VERSION 5.7 ;
  NOWIREEXTENSIONATPIN ON ;
  DIVIDERCHAR "/" ;
  BUSBITCHARS "[]" ;
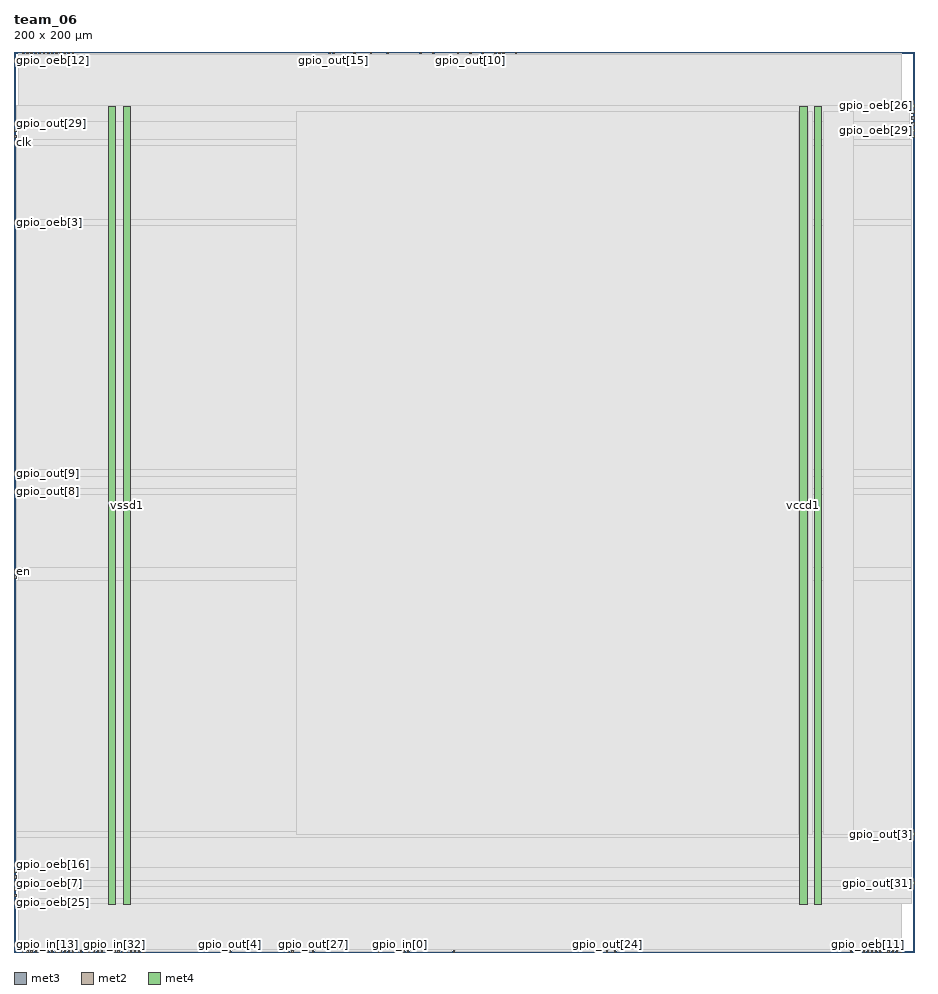
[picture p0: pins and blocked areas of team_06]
MACRO team_06
  CLASS BLOCK ;
  FOREIGN team_06 ;
  ORIGIN 0.000 0.000 ;
  SIZE 200.000 BY 200.000 ;
  PIN clk
    DIRECTION INPUT ;
    USE SIGNAL ;
    ANTENNAGATEAREA 1.286700 ;
    ANTENNADIFFAREA 0.434700 ;
    PORT
      LAYER met3 ;
        RECT 0.000 179.560 0.600 180.160 ;
    END
  END clk
  PIN en
    DIRECTION INPUT ;
    USE SIGNAL ;
    ANTENNAGATEAREA 0.647700 ;
    ANTENNADIFFAREA 0.434700 ;
    PORT
      LAYER met3 ;
        RECT 0.000 84.360 0.600 84.960 ;
    END
  END en
  PIN gpio_in[0]
    DIRECTION INPUT ;
    USE SIGNAL ;
    ANTENNAGATEAREA 0.647700 ;
    ANTENNADIFFAREA 0.434700 ;
    PORT
      LAYER met2 ;
        RECT 85.650 0.000 85.930 0.280 ;
    END
  END gpio_in[0]
  PIN gpio_in[10]
    DIRECTION INPUT ;
    USE SIGNAL ;
    PORT
      LAYER met2 ;
        RECT 1.930 0.000 2.210 0.280 ;
    END
  END gpio_in[10]
  PIN gpio_in[11]
    DIRECTION INPUT ;
    USE SIGNAL ;
    PORT
      LAYER met2 ;
        RECT 2.850 0.000 3.130 0.280 ;
    END
  END gpio_in[11]
  PIN gpio_in[12]
    DIRECTION INPUT ;
    USE SIGNAL ;
    PORT
      LAYER met2 ;
        RECT 3.770 0.000 4.050 0.280 ;
    END
  END gpio_in[12]
  PIN gpio_in[13]
    DIRECTION INPUT ;
    USE SIGNAL ;
    PORT
      LAYER met2 ;
        RECT 4.690 0.000 4.970 0.280 ;
    END
  END gpio_in[13]
  PIN gpio_in[14]
    DIRECTION INPUT ;
    USE SIGNAL ;
    PORT
      LAYER met2 ;
        RECT 5.610 0.000 5.890 0.280 ;
    END
  END gpio_in[14]
  PIN gpio_in[15]
    DIRECTION INPUT ;
    USE SIGNAL ;
    PORT
      LAYER met2 ;
        RECT 6.530 0.000 6.810 0.280 ;
    END
  END gpio_in[15]
  PIN gpio_in[16]
    DIRECTION INPUT ;
    USE SIGNAL ;
    PORT
      LAYER met2 ;
        RECT 7.450 0.000 7.730 0.280 ;
    END
  END gpio_in[16]
  PIN gpio_in[17]
    DIRECTION INPUT ;
    USE SIGNAL ;
    PORT
      LAYER met2 ;
        RECT 8.370 0.000 8.650 0.280 ;
    END
  END gpio_in[17]
  PIN gpio_in[18]
    DIRECTION INPUT ;
    USE SIGNAL ;
    PORT
      LAYER met2 ;
        RECT 9.290 0.000 9.570 0.280 ;
    END
  END gpio_in[18]
  PIN gpio_in[19]
    DIRECTION INPUT ;
    USE SIGNAL ;
    PORT
      LAYER met2 ;
        RECT 10.210 0.000 10.490 0.280 ;
    END
  END gpio_in[19]
  PIN gpio_in[1]
    DIRECTION INPUT ;
    USE SIGNAL ;
    ANTENNAGATEAREA 0.647700 ;
    ANTENNADIFFAREA 0.434700 ;
    PORT
      LAYER met2 ;
        RECT 81.050 0.000 81.330 0.280 ;
    END
  END gpio_in[1]
  PIN gpio_in[20]
    DIRECTION INPUT ;
    USE SIGNAL ;
    PORT
      LAYER met2 ;
        RECT 11.130 0.000 11.410 0.280 ;
    END
  END gpio_in[20]
  PIN gpio_in[21]
    DIRECTION INPUT ;
    USE SIGNAL ;
    PORT
      LAYER met2 ;
        RECT 12.050 0.000 12.330 0.280 ;
    END
  END gpio_in[21]
  PIN gpio_in[22]
    DIRECTION INPUT ;
    USE SIGNAL ;
    PORT
      LAYER met2 ;
        RECT 12.970 0.000 13.250 0.280 ;
    END
  END gpio_in[22]
  PIN gpio_in[23]
    DIRECTION INPUT ;
    USE SIGNAL ;
    PORT
      LAYER met2 ;
        RECT 13.890 0.000 14.170 0.280 ;
    END
  END gpio_in[23]
  PIN gpio_in[24]
    DIRECTION INPUT ;
    USE SIGNAL ;
    PORT
      LAYER met2 ;
        RECT 14.810 0.000 15.090 0.280 ;
    END
  END gpio_in[24]
  PIN gpio_in[25]
    DIRECTION INPUT ;
    USE SIGNAL ;
    PORT
      LAYER met2 ;
        RECT 15.730 0.000 16.010 0.280 ;
    END
  END gpio_in[25]
  PIN gpio_in[26]
    DIRECTION INPUT ;
    USE SIGNAL ;
    PORT
      LAYER met2 ;
        RECT 16.650 0.000 16.930 0.280 ;
    END
  END gpio_in[26]
  PIN gpio_in[27]
    DIRECTION INPUT ;
    USE SIGNAL ;
    PORT
      LAYER met2 ;
        RECT 17.570 0.000 17.850 0.280 ;
    END
  END gpio_in[27]
  PIN gpio_in[28]
    DIRECTION INPUT ;
    USE SIGNAL ;
    PORT
      LAYER met2 ;
        RECT 18.490 0.000 18.770 0.280 ;
    END
  END gpio_in[28]
  PIN gpio_in[29]
    DIRECTION INPUT ;
    USE SIGNAL ;
    PORT
      LAYER met2 ;
        RECT 19.410 0.000 19.690 0.280 ;
    END
  END gpio_in[29]
  PIN gpio_in[2]
    DIRECTION INPUT ;
    USE SIGNAL ;
    ANTENNAGATEAREA 0.647700 ;
    ANTENNADIFFAREA 0.434700 ;
    PORT
      LAYER met2 ;
        RECT 86.570 0.000 86.850 0.280 ;
    END
  END gpio_in[2]
  PIN gpio_in[30]
    DIRECTION INPUT ;
    USE SIGNAL ;
    PORT
      LAYER met2 ;
        RECT 20.330 0.000 20.610 0.280 ;
    END
  END gpio_in[30]
  PIN gpio_in[31]
    DIRECTION INPUT ;
    USE SIGNAL ;
    PORT
      LAYER met2 ;
        RECT 21.250 0.000 21.530 0.280 ;
    END
  END gpio_in[31]
  PIN gpio_in[32]
    DIRECTION INPUT ;
    USE SIGNAL ;
    PORT
      LAYER met2 ;
        RECT 22.170 0.000 22.450 0.280 ;
    END
  END gpio_in[32]
  PIN gpio_in[33]
    DIRECTION INPUT ;
    USE SIGNAL ;
    PORT
      LAYER met2 ;
        RECT 23.090 0.000 23.370 0.280 ;
    END
  END gpio_in[33]
  PIN gpio_in[3]
    DIRECTION INPUT ;
    USE SIGNAL ;
    ANTENNAGATEAREA 0.647700 ;
    ANTENNADIFFAREA 0.434700 ;
    PORT
      LAYER met2 ;
        RECT 87.490 0.000 87.770 0.280 ;
    END
  END gpio_in[3]
  PIN gpio_in[4]
    DIRECTION INPUT ;
    USE SIGNAL ;
    PORT
      LAYER met2 ;
        RECT 24.010 0.000 24.290 0.280 ;
    END
  END gpio_in[4]
  PIN gpio_in[5]
    DIRECTION INPUT ;
    USE SIGNAL ;
    PORT
      LAYER met2 ;
        RECT 24.930 0.000 25.210 0.280 ;
    END
  END gpio_in[5]
  PIN gpio_in[6]
    DIRECTION INPUT ;
    USE SIGNAL ;
    PORT
      LAYER met2 ;
        RECT 25.850 0.000 26.130 0.280 ;
    END
  END gpio_in[6]
  PIN gpio_in[7]
    DIRECTION INPUT ;
    USE SIGNAL ;
    PORT
      LAYER met2 ;
        RECT 26.770 0.000 27.050 0.280 ;
    END
  END gpio_in[7]
  PIN gpio_in[8]
    DIRECTION INPUT ;
    USE SIGNAL ;
    PORT
      LAYER met2 ;
        RECT 27.690 0.000 27.970 0.280 ;
    END
  END gpio_in[8]
  PIN gpio_in[9]
    DIRECTION INPUT ;
    USE SIGNAL ;
    PORT
      LAYER met2 ;
        RECT 28.610 0.000 28.890 0.280 ;
    END
  END gpio_in[9]
  PIN gpio_oeb[0]
    DIRECTION OUTPUT ;
    USE SIGNAL ;
    PORT
      LAYER met2 ;
        RECT 3.770 199.720 4.050 200.000 ;
    END
  END gpio_oeb[0]
  PIN gpio_oeb[10]
    DIRECTION OUTPUT ;
    USE SIGNAL ;
    PORT
      LAYER met2 ;
        RECT 9.290 199.720 9.570 200.000 ;
    END
  END gpio_oeb[10]
  PIN gpio_oeb[11]
    DIRECTION OUTPUT ;
    USE SIGNAL ;
    PORT
      LAYER met2 ;
        RECT 189.610 0.000 189.890 0.280 ;
    END
  END gpio_oeb[11]
  PIN gpio_oeb[12]
    DIRECTION OUTPUT ;
    USE SIGNAL ;
    PORT
      LAYER met2 ;
        RECT 5.610 199.720 5.890 200.000 ;
    END
  END gpio_oeb[12]
  PIN gpio_oeb[13]
    DIRECTION OUTPUT ;
    USE SIGNAL ;
    PORT
      LAYER met2 ;
        RECT 12.970 199.720 13.250 200.000 ;
    END
  END gpio_oeb[13]
  PIN gpio_oeb[14]
    DIRECTION OUTPUT ;
    USE SIGNAL ;
    PORT
      LAYER met2 ;
        RECT 196.970 0.000 197.250 0.280 ;
    END
  END gpio_oeb[14]
  PIN gpio_oeb[15]
    DIRECTION OUTPUT ;
    USE SIGNAL ;
    PORT
      LAYER met2 ;
        RECT 191.450 0.000 191.730 0.280 ;
    END
  END gpio_oeb[15]
  PIN gpio_oeb[16]
    DIRECTION OUTPUT ;
    USE SIGNAL ;
    PORT
      LAYER met3 ;
        RECT 0.000 17.720 0.600 18.320 ;
    END
  END gpio_oeb[16]
  PIN gpio_oeb[17]
    DIRECTION OUTPUT ;
    USE SIGNAL ;
    PORT
      LAYER met2 ;
        RECT 6.530 199.720 6.810 200.000 ;
    END
  END gpio_oeb[17]
  PIN gpio_oeb[18]
    DIRECTION OUTPUT ;
    USE SIGNAL ;
    PORT
      LAYER met2 ;
        RECT 11.130 199.720 11.410 200.000 ;
    END
  END gpio_oeb[18]
  PIN gpio_oeb[19]
    DIRECTION OUTPUT ;
    USE SIGNAL ;
    PORT
      LAYER met2 ;
        RECT 188.690 0.000 188.970 0.280 ;
    END
  END gpio_oeb[19]
  PIN gpio_oeb[1]
    DIRECTION OUTPUT ;
    USE SIGNAL ;
    PORT
      LAYER met2 ;
        RECT 185.930 0.000 186.210 0.280 ;
    END
  END gpio_oeb[1]
  PIN gpio_oeb[20]
    DIRECTION OUTPUT ;
    USE SIGNAL ;
    PORT
      LAYER met2 ;
        RECT 4.690 199.720 4.970 200.000 ;
    END
  END gpio_oeb[20]
  PIN gpio_oeb[21]
    DIRECTION OUTPUT ;
    USE SIGNAL ;
    PORT
      LAYER met2 ;
        RECT 192.370 0.000 192.650 0.280 ;
    END
  END gpio_oeb[21]
  PIN gpio_oeb[22]
    DIRECTION OUTPUT ;
    USE SIGNAL ;
    PORT
      LAYER met2 ;
        RECT 12.050 199.720 12.330 200.000 ;
    END
  END gpio_oeb[22]
  PIN gpio_oeb[23]
    DIRECTION OUTPUT ;
    USE SIGNAL ;
    PORT
      LAYER met2 ;
        RECT 2.850 199.720 3.130 200.000 ;
    END
  END gpio_oeb[23]
  PIN gpio_oeb[24]
    DIRECTION OUTPUT ;
    USE SIGNAL ;
    PORT
      LAYER met2 ;
        RECT 10.210 199.720 10.490 200.000 ;
    END
  END gpio_oeb[24]
  PIN gpio_oeb[25]
    DIRECTION OUTPUT ;
    USE SIGNAL ;
    PORT
      LAYER met3 ;
        RECT 0.000 12.280 0.600 12.880 ;
    END
  END gpio_oeb[25]
  PIN gpio_oeb[26]
    DIRECTION OUTPUT ;
    USE SIGNAL ;
    PORT
      LAYER met3 ;
        RECT 199.400 187.720 200.000 188.320 ;
    END
  END gpio_oeb[26]
  PIN gpio_oeb[27]
    DIRECTION OUTPUT ;
    USE SIGNAL ;
    PORT
      LAYER met2 ;
        RECT 195.130 0.000 195.410 0.280 ;
    END
  END gpio_oeb[27]
  PIN gpio_oeb[28]
    DIRECTION OUTPUT ;
    USE SIGNAL ;
    PORT
      LAYER met2 ;
        RECT 196.050 0.000 196.330 0.280 ;
    END
  END gpio_oeb[28]
  PIN gpio_oeb[29]
    DIRECTION OUTPUT ;
    USE SIGNAL ;
    PORT
      LAYER met3 ;
        RECT 199.400 182.280 200.000 182.880 ;
    END
  END gpio_oeb[29]
  PIN gpio_oeb[2]
    DIRECTION OUTPUT ;
    USE SIGNAL ;
    PORT
      LAYER met2 ;
        RECT 1.930 199.720 2.210 200.000 ;
    END
  END gpio_oeb[2]
  PIN gpio_oeb[30]
    DIRECTION OUTPUT ;
    USE SIGNAL ;
    PORT
      LAYER met2 ;
        RECT 7.450 199.720 7.730 200.000 ;
    END
  END gpio_oeb[30]
  PIN gpio_oeb[31]
    DIRECTION OUTPUT ;
    USE SIGNAL ;
    PORT
      LAYER met2 ;
        RECT 187.770 0.000 188.050 0.280 ;
    END
  END gpio_oeb[31]
  PIN gpio_oeb[32]
    DIRECTION OUTPUT ;
    USE SIGNAL ;
    PORT
      LAYER met2 ;
        RECT 186.850 0.000 187.130 0.280 ;
    END
  END gpio_oeb[32]
  PIN gpio_oeb[33]
    DIRECTION OUTPUT ;
    USE SIGNAL ;
    PORT
      LAYER met2 ;
        RECT 8.370 199.720 8.650 200.000 ;
    END
  END gpio_oeb[33]
  PIN gpio_oeb[3]
    DIRECTION OUTPUT ;
    USE SIGNAL ;
    PORT
      LAYER met3 ;
        RECT 0.000 161.880 0.600 162.480 ;
    END
  END gpio_oeb[3]
  PIN gpio_oeb[4]
    DIRECTION OUTPUT ;
    USE SIGNAL ;
    PORT
      LAYER met2 ;
        RECT 190.530 0.000 190.810 0.280 ;
    END
  END gpio_oeb[4]
  PIN gpio_oeb[5]
    DIRECTION OUTPUT ;
    USE SIGNAL ;
    PORT
      LAYER met2 ;
        RECT 194.210 0.000 194.490 0.280 ;
    END
  END gpio_oeb[5]
  PIN gpio_oeb[6]
    DIRECTION OUTPUT ;
    USE SIGNAL ;
    PORT
      LAYER met3 ;
        RECT 199.400 183.640 200.000 184.240 ;
    END
  END gpio_oeb[6]
  PIN gpio_oeb[7]
    DIRECTION OUTPUT ;
    USE SIGNAL ;
    PORT
      LAYER met3 ;
        RECT 0.000 15.000 0.600 15.600 ;
    END
  END gpio_oeb[7]
  PIN gpio_oeb[8]
    DIRECTION OUTPUT ;
    USE SIGNAL ;
    PORT
      LAYER met3 ;
        RECT 199.400 186.360 200.000 186.960 ;
    END
  END gpio_oeb[8]
  PIN gpio_oeb[9]
    DIRECTION OUTPUT ;
    USE SIGNAL ;
    PORT
      LAYER met2 ;
        RECT 193.290 0.000 193.570 0.280 ;
    END
  END gpio_oeb[9]
  PIN gpio_out[0]
    DIRECTION OUTPUT ;
    USE SIGNAL ;
    PORT
      LAYER met3 ;
        RECT 199.400 185.000 200.000 185.600 ;
    END
  END gpio_out[0]
  PIN gpio_out[10]
    DIRECTION OUTPUT ;
    USE SIGNAL ;
    ANTENNADIFFAREA 0.702900 ;
    PORT
      LAYER met2 ;
        RECT 101.290 199.720 101.570 200.000 ;
    END
  END gpio_out[10]
  PIN gpio_out[11]
    DIRECTION OUTPUT ;
    USE SIGNAL ;
    ANTENNADIFFAREA 0.702900 ;
    PORT
      LAYER met2 ;
        RECT 98.530 199.720 98.810 200.000 ;
    END
  END gpio_out[11]
  PIN gpio_out[12]
    DIRECTION OUTPUT ;
    USE SIGNAL ;
    ANTENNADIFFAREA 0.702900 ;
    PORT
      LAYER met2 ;
        RECT 79.210 199.720 79.490 200.000 ;
    END
  END gpio_out[12]
  PIN gpio_out[13]
    DIRECTION OUTPUT ;
    USE SIGNAL ;
    ANTENNADIFFAREA 0.702900 ;
    PORT
      LAYER met2 ;
        RECT 82.890 199.720 83.170 200.000 ;
    END
  END gpio_out[13]
  PIN gpio_out[14]
    DIRECTION OUTPUT ;
    USE SIGNAL ;
    ANTENNADIFFAREA 0.702900 ;
    PORT
      LAYER met2 ;
        RECT 90.250 199.720 90.530 200.000 ;
    END
  END gpio_out[14]
  PIN gpio_out[15]
    DIRECTION OUTPUT ;
    USE SIGNAL ;
    ANTENNADIFFAREA 0.702900 ;
    PORT
      LAYER met2 ;
        RECT 70.930 199.720 71.210 200.000 ;
    END
  END gpio_out[15]
  PIN gpio_out[16]
    DIRECTION OUTPUT ;
    USE SIGNAL ;
    ANTENNADIFFAREA 0.702900 ;
    PORT
      LAYER met2 ;
        RECT 93.010 199.720 93.290 200.000 ;
    END
  END gpio_out[16]
  PIN gpio_out[17]
    DIRECTION OUTPUT ;
    USE SIGNAL ;
    ANTENNADIFFAREA 0.702900 ;
    PORT
      LAYER met2 ;
        RECT 75.530 199.720 75.810 200.000 ;
    END
  END gpio_out[17]
  PIN gpio_out[18]
    DIRECTION OUTPUT ;
    USE SIGNAL ;
    ANTENNADIFFAREA 0.702900 ;
    PORT
      LAYER met2 ;
        RECT 70.010 199.720 70.290 200.000 ;
    END
  END gpio_out[18]
  PIN gpio_out[19]
    DIRECTION OUTPUT ;
    USE SIGNAL ;
    ANTENNADIFFAREA 0.702900 ;
    PORT
      LAYER met2 ;
        RECT 104.050 199.720 104.330 200.000 ;
    END
  END gpio_out[19]
  PIN gpio_out[1]
    DIRECTION OUTPUT ;
    USE SIGNAL ;
    PORT
      LAYER met3 ;
        RECT 0.000 13.640 0.600 14.240 ;
    END
  END gpio_out[1]
  PIN gpio_out[20]
    DIRECTION OUTPUT ;
    USE SIGNAL ;
    ANTENNADIFFAREA 0.702900 ;
    PORT
      LAYER met2 ;
        RECT 111.410 199.720 111.690 200.000 ;
    END
  END gpio_out[20]
  PIN gpio_out[21]
    DIRECTION OUTPUT ;
    USE SIGNAL ;
    ANTENNADIFFAREA 0.702900 ;
    PORT
      LAYER met2 ;
        RECT 106.810 199.720 107.090 200.000 ;
    END
  END gpio_out[21]
  PIN gpio_out[22]
    DIRECTION OUTPUT ;
    USE SIGNAL ;
    ANTENNADIFFAREA 0.702900 ;
    PORT
      LAYER met2 ;
        RECT 108.650 199.720 108.930 200.000 ;
    END
  END gpio_out[22]
  PIN gpio_out[23]
    DIRECTION OUTPUT ;
    USE SIGNAL ;
    ANTENNADIFFAREA 0.702900 ;
    PORT
      LAYER met2 ;
        RECT 107.730 199.720 108.010 200.000 ;
    END
  END gpio_out[23]
  PIN gpio_out[24]
    DIRECTION OUTPUT ;
    USE SIGNAL ;
    ANTENNADIFFAREA 0.702900 ;
    PORT
      LAYER met2 ;
        RECT 131.650 0.000 131.930 0.280 ;
    END
  END gpio_out[24]
  PIN gpio_out[25]
    DIRECTION OUTPUT ;
    USE SIGNAL ;
    ANTENNADIFFAREA 0.702900 ;
    PORT
      LAYER met2 ;
        RECT 133.490 0.000 133.770 0.280 ;
    END
  END gpio_out[25]
  PIN gpio_out[26]
    DIRECTION OUTPUT ;
    USE SIGNAL ;
    ANTENNADIFFAREA 0.702900 ;
    PORT
      LAYER met2 ;
        RECT 129.810 0.000 130.090 0.280 ;
    END
  END gpio_out[26]
  PIN gpio_out[27]
    DIRECTION OUTPUT ;
    USE SIGNAL ;
    ANTENNADIFFAREA 0.702900 ;
    PORT
      LAYER met2 ;
        RECT 66.330 0.000 66.610 0.280 ;
    END
  END gpio_out[27]
  PIN gpio_out[28]
    DIRECTION OUTPUT ;
    USE SIGNAL ;
    ANTENNADIFFAREA 0.702900 ;
    PORT
      LAYER met2 ;
        RECT 97.610 0.000 97.890 0.280 ;
    END
  END gpio_out[28]
  PIN gpio_out[29]
    DIRECTION OUTPUT ;
    USE SIGNAL ;
    PORT
      LAYER met3 ;
        RECT 0.000 182.280 0.600 182.880 ;
    END
  END gpio_out[29]
  PIN gpio_out[2]
    DIRECTION OUTPUT ;
    USE SIGNAL ;
    PORT
      LAYER met3 ;
        RECT 199.400 180.920 200.000 181.520 ;
    END
  END gpio_out[2]
  PIN gpio_out[30]
    DIRECTION OUTPUT ;
    USE SIGNAL ;
    PORT
      LAYER met3 ;
        RECT 0.000 183.640 0.600 184.240 ;
    END
  END gpio_out[30]
  PIN gpio_out[31]
    DIRECTION OUTPUT ;
    USE SIGNAL ;
    PORT
      LAYER met3 ;
        RECT 199.400 15.000 200.000 15.600 ;
    END
  END gpio_out[31]
  PIN gpio_out[32]
    DIRECTION OUTPUT ;
    USE SIGNAL ;
    PORT
      LAYER met3 ;
        RECT 0.000 180.920 0.600 181.520 ;
    END
  END gpio_out[32]
  PIN gpio_out[33]
    DIRECTION OUTPUT ;
    USE SIGNAL ;
    PORT
      LAYER met3 ;
        RECT 0.000 16.360 0.600 16.960 ;
    END
  END gpio_out[33]
  PIN gpio_out[3]
    DIRECTION OUTPUT ;
    USE SIGNAL ;
    PORT
      LAYER met3 ;
        RECT 199.400 25.880 200.000 26.480 ;
    END
  END gpio_out[3]
  PIN gpio_out[4]
    DIRECTION OUTPUT ;
    USE SIGNAL ;
    ANTENNADIFFAREA 0.702900 ;
    PORT
      LAYER met2 ;
        RECT 47.930 0.000 48.210 0.280 ;
    END
  END gpio_out[4]
  PIN gpio_out[5]
    DIRECTION OUTPUT ;
    USE SIGNAL ;
    ANTENNADIFFAREA 0.702900 ;
    PORT
      LAYER met2 ;
        RECT 60.810 0.000 61.090 0.280 ;
    END
  END gpio_out[5]
  PIN gpio_out[6]
    DIRECTION OUTPUT ;
    USE SIGNAL ;
    ANTENNADIFFAREA 0.702900 ;
    PORT
      LAYER met2 ;
        RECT 65.410 0.000 65.690 0.280 ;
    END
  END gpio_out[6]
  PIN gpio_out[7]
    DIRECTION OUTPUT ;
    USE SIGNAL ;
    ANTENNADIFFAREA 0.702900 ;
    PORT
      LAYER met2 ;
        RECT 61.730 0.000 62.010 0.280 ;
    END
  END gpio_out[7]
  PIN gpio_out[8]
    DIRECTION OUTPUT ;
    USE SIGNAL ;
    ANTENNADIFFAREA 0.702900 ;
    PORT
      LAYER met3 ;
        RECT 0.000 102.040 0.600 102.640 ;
    END
  END gpio_out[8]
  PIN gpio_out[9]
    DIRECTION OUTPUT ;
    USE SIGNAL ;
    ANTENNADIFFAREA 0.702900 ;
    PORT
      LAYER met3 ;
        RECT 0.000 106.120 0.600 106.720 ;
    END
  END gpio_out[9]
  PIN nrst
    DIRECTION INPUT ;
    USE SIGNAL ;
    ANTENNAGATEAREA 0.647700 ;
    ANTENNADIFFAREA 0.434700 ;
    PORT
      LAYER met3 ;
        RECT 0.000 83.000 0.600 83.600 ;
    END
  END nrst
  PIN vccd1
    DIRECTION INOUT ;
    USE POWER ;
    PORT
      LAYER met4 ;
        RECT 21.040 10.640 22.640 187.920 ;
    END
    PORT
      LAYER met4 ;
        RECT 174.640 10.640 176.240 187.920 ;
    END
  END vccd1
  PIN vssd1
    DIRECTION INOUT ;
    USE GROUND ;
    PORT
      LAYER met4 ;
        RECT 24.340 10.640 25.940 187.920 ;
    END
    PORT
      LAYER met4 ;
        RECT 177.940 10.640 179.540 187.920 ;
    END
  END vssd1
  OBS
      LAYER nwell ;
        RECT 5.330 10.760 194.310 187.870 ;
      LAYER li1 ;
        RECT 5.520 10.795 194.120 187.765 ;
      LAYER met1 ;
        RECT 0.990 1.060 197.270 194.780 ;
      LAYER met2 ;
        RECT 1.010 199.440 1.650 199.720 ;
        RECT 2.490 199.440 2.570 199.720 ;
        RECT 3.410 199.440 3.490 199.720 ;
        RECT 4.330 199.440 4.410 199.720 ;
        RECT 5.250 199.440 5.330 199.720 ;
        RECT 6.170 199.440 6.250 199.720 ;
        RECT 7.090 199.440 7.170 199.720 ;
        RECT 8.010 199.440 8.090 199.720 ;
        RECT 8.930 199.440 9.010 199.720 ;
        RECT 9.850 199.440 9.930 199.720 ;
        RECT 10.770 199.440 10.850 199.720 ;
        RECT 11.690 199.440 11.770 199.720 ;
        RECT 12.610 199.440 12.690 199.720 ;
        RECT 13.530 199.440 69.730 199.720 ;
        RECT 70.570 199.440 70.650 199.720 ;
        RECT 71.490 199.440 75.250 199.720 ;
        RECT 76.090 199.440 78.930 199.720 ;
        RECT 79.770 199.440 82.610 199.720 ;
        RECT 83.450 199.440 89.970 199.720 ;
        RECT 90.810 199.440 92.730 199.720 ;
        RECT 93.570 199.440 98.250 199.720 ;
        RECT 99.090 199.440 101.010 199.720 ;
        RECT 101.850 199.440 103.770 199.720 ;
        RECT 104.610 199.440 106.530 199.720 ;
        RECT 107.370 199.440 107.450 199.720 ;
        RECT 108.290 199.440 108.370 199.720 ;
        RECT 109.210 199.440 111.130 199.720 ;
        RECT 111.970 199.440 197.240 199.720 ;
        RECT 1.010 0.560 197.240 199.440 ;
        RECT 1.010 0.070 1.650 0.560 ;
        RECT 2.490 0.070 2.570 0.560 ;
        RECT 3.410 0.070 3.490 0.560 ;
        RECT 4.330 0.070 4.410 0.560 ;
        RECT 5.250 0.070 5.330 0.560 ;
        RECT 6.170 0.070 6.250 0.560 ;
        RECT 7.090 0.070 7.170 0.560 ;
        RECT 8.010 0.070 8.090 0.560 ;
        RECT 8.930 0.070 9.010 0.560 ;
        RECT 9.850 0.070 9.930 0.560 ;
        RECT 10.770 0.070 10.850 0.560 ;
        RECT 11.690 0.070 11.770 0.560 ;
        RECT 12.610 0.070 12.690 0.560 ;
        RECT 13.530 0.070 13.610 0.560 ;
        RECT 14.450 0.070 14.530 0.560 ;
        RECT 15.370 0.070 15.450 0.560 ;
        RECT 16.290 0.070 16.370 0.560 ;
        RECT 17.210 0.070 17.290 0.560 ;
        RECT 18.130 0.070 18.210 0.560 ;
        RECT 19.050 0.070 19.130 0.560 ;
        RECT 19.970 0.070 20.050 0.560 ;
        RECT 20.890 0.070 20.970 0.560 ;
        RECT 21.810 0.070 21.890 0.560 ;
        RECT 22.730 0.070 22.810 0.560 ;
        RECT 23.650 0.070 23.730 0.560 ;
        RECT 24.570 0.070 24.650 0.560 ;
        RECT 25.490 0.070 25.570 0.560 ;
        RECT 26.410 0.070 26.490 0.560 ;
        RECT 27.330 0.070 27.410 0.560 ;
        RECT 28.250 0.070 28.330 0.560 ;
        RECT 29.170 0.070 47.650 0.560 ;
        RECT 48.490 0.070 60.530 0.560 ;
        RECT 61.370 0.070 61.450 0.560 ;
        RECT 62.290 0.070 65.130 0.560 ;
        RECT 65.970 0.070 66.050 0.560 ;
        RECT 66.890 0.070 80.770 0.560 ;
        RECT 81.610 0.070 85.370 0.560 ;
        RECT 86.210 0.070 86.290 0.560 ;
        RECT 87.130 0.070 87.210 0.560 ;
        RECT 88.050 0.070 97.330 0.560 ;
        RECT 98.170 0.070 129.530 0.560 ;
        RECT 130.370 0.070 131.370 0.560 ;
        RECT 132.210 0.070 133.210 0.560 ;
        RECT 134.050 0.070 185.650 0.560 ;
        RECT 186.490 0.070 186.570 0.560 ;
        RECT 187.410 0.070 187.490 0.560 ;
        RECT 188.330 0.070 188.410 0.560 ;
        RECT 189.250 0.070 189.330 0.560 ;
        RECT 190.170 0.070 190.250 0.560 ;
        RECT 191.090 0.070 191.170 0.560 ;
        RECT 192.010 0.070 192.090 0.560 ;
        RECT 192.930 0.070 193.010 0.560 ;
        RECT 193.850 0.070 193.930 0.560 ;
        RECT 194.770 0.070 194.850 0.560 ;
        RECT 195.690 0.070 195.770 0.560 ;
        RECT 196.610 0.070 196.690 0.560 ;
      LAYER met3 ;
        RECT 0.600 184.640 199.000 188.185 ;
        RECT 1.000 180.520 199.000 184.640 ;
        RECT 1.000 179.160 199.400 180.520 ;
        RECT 0.600 162.880 199.400 179.160 ;
        RECT 1.000 161.480 199.400 162.880 ;
        RECT 0.600 107.120 199.400 161.480 ;
        RECT 1.000 105.720 199.400 107.120 ;
        RECT 0.600 103.040 199.400 105.720 ;
        RECT 1.000 101.640 199.400 103.040 ;
        RECT 0.600 85.360 199.400 101.640 ;
        RECT 1.000 82.600 199.400 85.360 ;
        RECT 0.600 26.880 199.400 82.600 ;
        RECT 0.600 25.480 199.000 26.880 ;
        RECT 0.600 18.720 199.400 25.480 ;
        RECT 1.000 16.000 199.400 18.720 ;
        RECT 1.000 14.600 199.000 16.000 ;
        RECT 1.000 11.880 199.400 14.600 ;
        RECT 0.600 10.715 199.400 11.880 ;
      LAYER met4 ;
        RECT 62.855 26.015 174.240 186.825 ;
        RECT 176.640 26.015 177.540 186.825 ;
        RECT 179.940 26.015 186.465 186.825 ;
  END
END team_06
END LIBRARY

